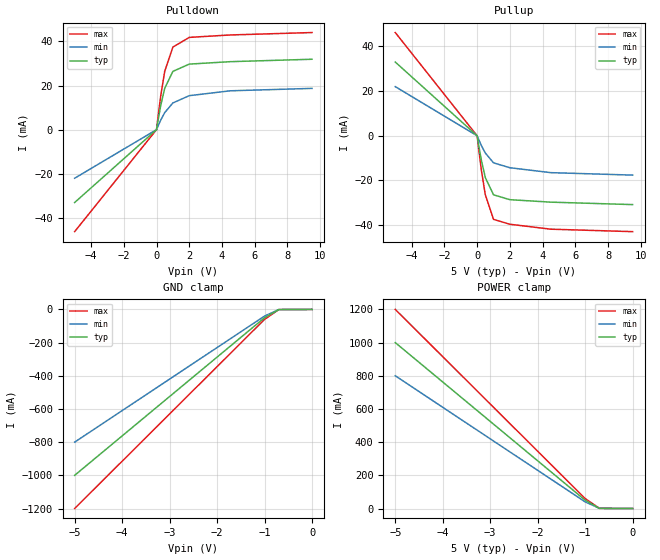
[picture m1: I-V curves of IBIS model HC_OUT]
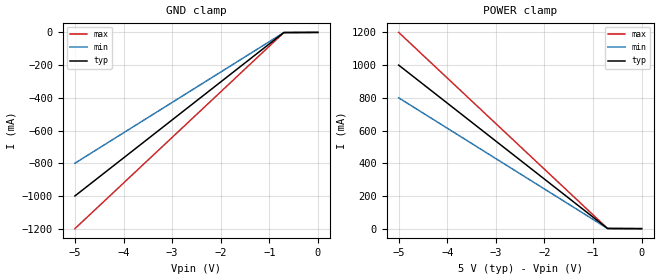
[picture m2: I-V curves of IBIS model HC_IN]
| DATASHEET-DERIVED IBIS — NOT A VENDOR FILE.
| 74HC-family CMOS I/O at the VCC = 5.0 V operating point, hand-derived
| by the bhdl stdlib data campaign from PUBLISHED specification points:
|   * TI SN74HC08 datasheet (SCLS081) / SN74HC00 (SCLS047). The
|   datasheet publishes TWO characterization columns (VCC = 4.5 V,
|   rated IOL 4 mA; VCC = 6 V, rated IOL 5.2 mA); the tables below
|   are INTERPOLATED to the VCC = 5.0 V operating point between
|   those two published columns (drive scale 4.4/4.0 = 1.10):
|   VOL 0.1 V typ at IOL = 4 mA (4.5 V col) -> 23 ohm slope at 5 V
|   VOL 0.26 V MAX at IOL = 4 mA -> 59 ohm min-corner slope
|   (the guaranteed-worst device)
|   VOH VCC-0.1 V typ at -4 mA   -> pullup mirrors pulldown
|   input capacitance 3.5 pF typ -> C_comp
|   transition time 8 ns typ / 15 ns max at CL = 50 pF -> [Ramp]
|   (20-80% swing = 0.6 x 5.0 V = 3.0 V; tt scales ~vcc^-0.5,
|   ~7.5 ns at 5 V)
|   * Saturation plateau (~28 mA typ at large Vout) from the 74HC family
|   typical output characteristics published in Nexperia's family
|   specifications (the classic HC output curve knee).
|   * max corner = typ scaled +40% (strong-process bound, stated
|   assumption — no published max-drive spec exists for this family).
|   * Clamp tables = standard CMOS protection-diode curve (0.7 V knee).
| Every simulation consuming this file inherits these provenance notes:
| the derivation is honest interpolation BETWEEN published points, never
| invention beyond them.
[IBIS Ver]   4.2
[File Name]  sn74hc_5v.ibs
[Component]  SN74HC08
[Manufacturer] bhdl derived (from TI SCLS081)
[Pin]  signal_name  model_name
1   A1   HC_IN
2   B1   HC_IN
3   Y1   HC_OUT
4   A2   HC_IN
5   B2   HC_IN
6   Y2   HC_OUT
7   GND   GND
8   Y3   HC_OUT
9   A3   HC_IN
10   B3   HC_IN
11   Y4   HC_OUT
12   A4   HC_IN
13   B4   HC_IN
14   VCC   POWER
[Component]  SN74HC00
[Manufacturer] bhdl derived (from TI SCLS047)
[Pin]  signal_name  model_name
1   A1   HC_IN
2   B1   HC_IN
3   Y1   HC_OUT
4   A2   HC_IN
5   B2   HC_IN
6   Y2   HC_OUT
7   GND   GND
8   Y3   HC_OUT
9   A3   HC_IN
10   B3   HC_IN
11   Y4   HC_OUT
12   A4   HC_IN
13   B4   HC_IN
14   VCC   POWER
[Component]  SN74HC595
[Manufacturer] bhdl derived (from TI SCLS041; outputs are the family
| bus-driver class, rated +/-6 mA — the HC_OUT stage below is the
| published-family-point model and CONSERVATIVE for them)
[Pin]  signal_name  model_name
1   QB   HC_OUT
2   QC   HC_OUT
3   QD   HC_OUT
4   QE   HC_OUT
5   QF   HC_OUT
6   QG   HC_OUT
7   QH   HC_OUT
8   GND   GND
9   QH_S   HC_OUT
10   SRCLR   HC_IN
11   SRCLK   HC_IN
12   RCLK   HC_IN
13   OE   HC_IN
14   SER   HC_IN
15   QA   HC_OUT
16   VCC   POWER
| Models and submodels in the file (2): HC_OUT (Output), HC_IN (Input)
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[Model]  HC_OUT
Model_type   Output
C_comp   3.5pF  3.5pF  3.5pF
[Voltage Range]  5.0V  4.5V  5.5V
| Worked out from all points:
|   slope of the pulldown table from 0 to 0.75 V, typ, clamps not added: 33.3 ohm
|   slope of the pullup table from 0 to 0.75 V, typ, clamps not added: 33.3 ohm
[Pulldown]
| Vout   I(typ)   I(min)   I(max)
| slope through the published VOL/IOL points, plateau at the family
| knee; min = the guaranteed-worst device (VOL max column, 59-ohm slope).
-5V       -33mA      -22mA      -46.2mA
0V        0A         0A         0A
100mV     4.4mA      1.7mA      6.2mA
260mV     11mA       4.4mA      15.4mA
500mV     18.7mA     7.7mA      26.4mA
1V        26.4mA     12.1mA     37.4mA
2V        29.7mA     15.4mA     41.8mA
4.5V      30.8mA     17.6mA     42.9mA
9.5V      31.9mA     18.7mA     44mA
[Pullup]
| V(=Vcc-Vpin)  I(typ)   I(min)   I(max)
-5V       33mA       22mA       46.2mA
0V        0A         0A         0A
100mV     -4.4mA     -1.7mA     -6.2mA
260mV     -11mA      -4.4mA     -15.4mA
500mV     -18.7mA    -7.7mA     -26.4mA
1V        -26.4mA    -12.1mA    -37.4mA
2V        -28.6mA    -14.3mA    -39.6mA
4.5V      -29.7mA    -16.5mA    -41.8mA
9.5V      -30.8mA    -17.6mA    -42.9mA
[GND Clamp]
| standard CMOS substrate diode, 0.7 V knee
-5V       -1A        -800mA     -1.2A
-1V       -50mA      -40mA      -60mA
-700mV    -1mA       -1mA       -1mA
0V        0A         0A         0A
[POWER Clamp]
-5V       1A         800mA      1.2A
-1V       50mA       40mA       60mA
-700mV    1mA        1mA        1mA
0V        0A         0A         0A
[Ramp]
| 20-80% of 5.0 V = 3.0 V over 0.75 x tt (tt ~7.5 ns typ at 5 V,
| interpolated from the 8 ns @ 4.5 V / 7 ns-class @ 6 V columns)
dV/dt_r   3.0/5.6n   3.0/10.5n  3.0/3.8n
dV/dt_f   3.0/5.6n   3.0/10.5n  3.0/3.8n
[Model]  HC_IN
Model_type   Input
C_comp   3.5pF  3.5pF  3.5pF
[Voltage Range]  5.0V  4.5V  5.5V
[GND Clamp]
-5V       -1A        -800mA     -1.2A
-700mV    -1mA       -1mA       -1mA
0V        0A         0A         0A
[POWER Clamp]
-5V       1A         800mA      1.2A
-700mV    1mA        1mA        1mA
0V        0A         0A         0A
